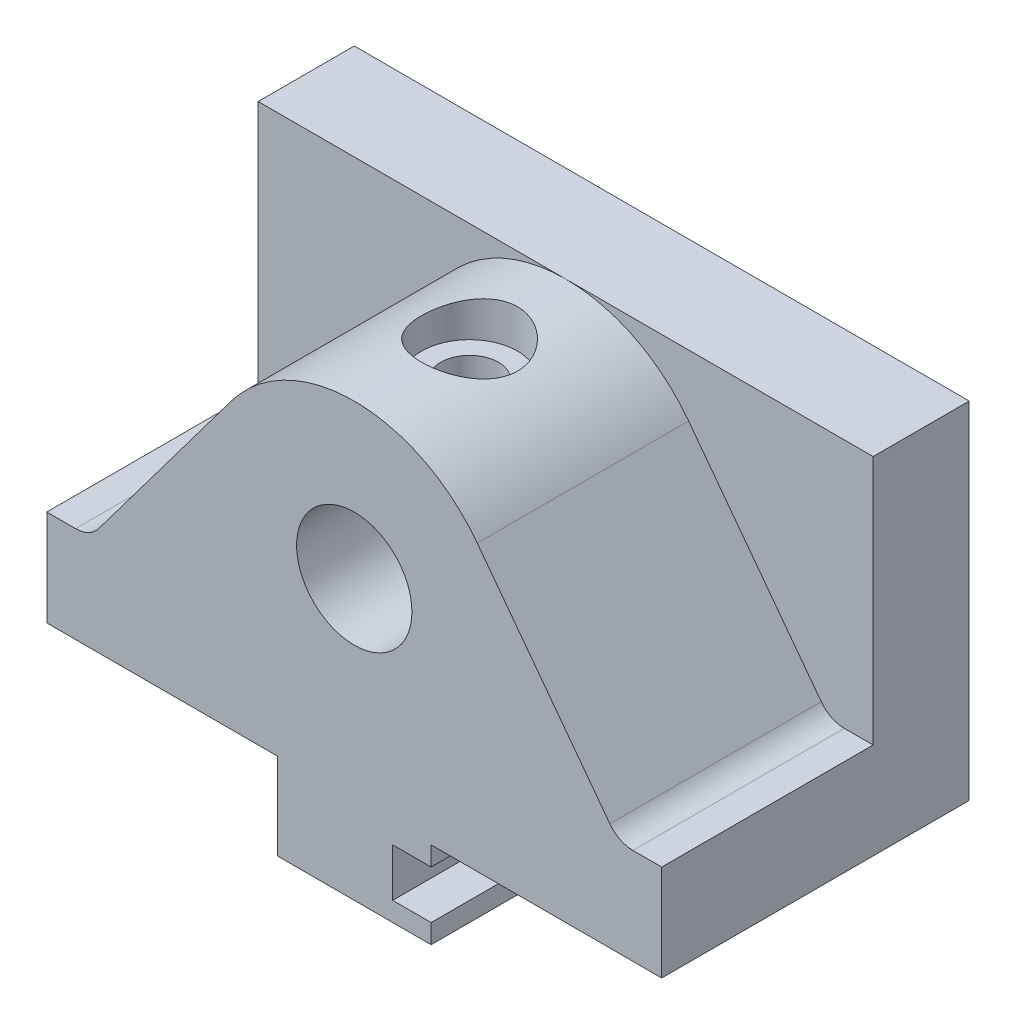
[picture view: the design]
ISO-10303-21;
HEADER;
FILE_DESCRIPTION(('STEP AP214'),'2;1');
FILE_NAME('part.step','',(''),(''),'','','');
FILE_SCHEMA(('AUTOMOTIVE_DESIGN { 1 0 10303 214 1 1 1 1 }'));
ENDSEC;
DATA;
#1=APPLICATION_CONTEXT('core data for automotive mechanical design processes');
#2=APPLICATION_PROTOCOL_DEFINITION('international standard','automotive_design',2000,#1);
#3=PRODUCT_CONTEXT('',#1,'mechanical');
#4=PRODUCT('Part','Part','',(#3));
#5=PRODUCT_RELATED_PRODUCT_CATEGORY('part','',(#4));
#6=PRODUCT_DEFINITION_FORMATION('','',#4);
#7=PRODUCT_DEFINITION_CONTEXT('part definition',#1,'design');
#8=PRODUCT_DEFINITION('design','',#6,#7);
#9=PRODUCT_DEFINITION_SHAPE('','',#8);
#10=(LENGTH_UNIT() NAMED_UNIT(*) SI_UNIT(.MILLI.,.METRE.));
#11=(NAMED_UNIT(*) PLANE_ANGLE_UNIT() SI_UNIT($,.RADIAN.));
#12=(NAMED_UNIT(*) SI_UNIT($,.STERADIAN.) SOLID_ANGLE_UNIT());
#13=UNCERTAINTY_MEASURE_WITH_UNIT(LENGTH_MEASURE(1.E-05),#10,'distance_accuracy_value','');
#14=(GEOMETRIC_REPRESENTATION_CONTEXT(3) GLOBAL_UNCERTAINTY_ASSIGNED_CONTEXT((#13)) GLOBAL_UNIT_ASSIGNED_CONTEXT((#10,
#11,#12)) REPRESENTATION_CONTEXT('',''));
#15=CARTESIAN_POINT('',(0.,0.,0.));
#16=DIRECTION('',(0.,0.,1.));
#17=DIRECTION('',(1.,0.,0.));
#18=AXIS2_PLACEMENT_3D('',#15,#16,#17);
#19=CARTESIAN_POINT('',(8.00000000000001,-14.,32.));
#20=DIRECTION('',(-1.,0.,0.));
#21=DIRECTION('',(0.,-1.,0.));
#22=AXIS2_PLACEMENT_3D('',#19,#20,#21);
#23=PLANE('',#22);
#24=DIRECTION('',(0.,1.,0.));
#25=VECTOR('',#24,1.);
#26=CARTESIAN_POINT('',(8.00000000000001,-14.,0.));
#27=LINE('',#26,#25);
#28=CARTESIAN_POINT('',(8.00000000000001,-23.,0.));
#29=VERTEX_POINT('',#28);
#30=CARTESIAN_POINT('',(8.00000000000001,-21.,0.));
#31=VERTEX_POINT('',#30);
#32=EDGE_CURVE('E383',#29,#31,#27,.T.);
#33=ORIENTED_EDGE('',*,*,#32,.T.);
#34=DIRECTION('',(0.,0.,1.));
#35=VECTOR('',#34,1.);
#36=CARTESIAN_POINT('',(8.00000000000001,-21.,0.));
#37=LINE('',#36,#35);
#38=CARTESIAN_POINT('',(8.00000000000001,-21.,32.));
#39=VERTEX_POINT('',#38);
#40=EDGE_CURVE('E406',#31,#39,#37,.T.);
#41=ORIENTED_EDGE('',*,*,#40,.T.);
#42=DIRECTION('',(0.,1.,0.));
#43=VECTOR('',#42,1.);
#44=CARTESIAN_POINT('',(8.00000000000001,-14.,32.));
#45=LINE('',#44,#43);
#46=CARTESIAN_POINT('',(8.00000000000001,-23.,32.));
#47=VERTEX_POINT('',#46);
#48=EDGE_CURVE('E209',#47,#39,#45,.T.);
#49=ORIENTED_EDGE('',*,*,#48,.F.);
#50=DIRECTION('',(0.,0.,-1.));
#51=VECTOR('',#50,1.);
#52=CARTESIAN_POINT('',(8.00000000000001,-23.,32.));
#53=LINE('',#52,#51);
#54=EDGE_CURVE('E222',#47,#29,#53,.T.);
#55=ORIENTED_EDGE('',*,*,#54,.T.);
#56=EDGE_LOOP('',(#33,#41,#49,#55));
#57=FACE_BOUND('',#56,.T.);
#58=ADVANCED_FACE('F29',(#57),#23,.F.);
#59=CARTESIAN_POINT('',(8.00000000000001,-23.,32.));
#60=DIRECTION('',(0.,1.,0.));
#61=DIRECTION('',(-1.,0.,0.));
#62=AXIS2_PLACEMENT_3D('',#59,#60,#61);
#63=PLANE('',#62);
#64=CARTESIAN_POINT('',(0.,-23.,24.));
#65=DIRECTION('',(0.,1.,0.));
#66=DIRECTION('',(-1.,0.,0.));
#67=AXIS2_PLACEMENT_3D('',#64,#65,#66);
#68=CIRCLE('',#67,3.);
#69=CARTESIAN_POINT('',(-2.99999999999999,-23.,24.));
#70=VERTEX_POINT('',#69);
#71=EDGE_CURVE('E429',#70,#70,#68,.T.);
#72=ORIENTED_EDGE('',*,*,#71,.T.);
#73=EDGE_LOOP('',(#72));
#74=FACE_BOUND('',#73,.T.);
#75=DIRECTION('',(1.,0.,0.));
#76=VECTOR('',#75,1.);
#77=CARTESIAN_POINT('',(8.00000000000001,-23.,0.));
#78=LINE('',#77,#76);
#79=CARTESIAN_POINT('',(-7.99999999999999,-23.,0.));
#80=VERTEX_POINT('',#79);
#81=EDGE_CURVE('E380',#80,#29,#78,.T.);
#82=ORIENTED_EDGE('',*,*,#81,.T.);
#83=ORIENTED_EDGE('',*,*,#54,.F.);
#84=DIRECTION('',(1.,0.,0.));
#85=VECTOR('',#84,1.);
#86=CARTESIAN_POINT('',(8.00000000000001,-23.,32.));
#87=LINE('',#86,#85);
#88=CARTESIAN_POINT('',(-7.99999999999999,-23.,32.));
#89=VERTEX_POINT('',#88);
#90=EDGE_CURVE('E210',#89,#47,#87,.T.);
#91=ORIENTED_EDGE('',*,*,#90,.F.);
#92=DIRECTION('',(0.,0.,-1.));
#93=VECTOR('',#92,1.);
#94=CARTESIAN_POINT('',(-7.99999999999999,-23.,32.));
#95=LINE('',#94,#93);
#96=EDGE_CURVE('E225',#89,#80,#95,.T.);
#97=ORIENTED_EDGE('',*,*,#96,.T.);
#98=EDGE_LOOP('',(#82,#83,#91,#97));
#99=FACE_BOUND('',#98,.T.);
#100=CARTESIAN_POINT('',(0.,-23.,8.));
#101=DIRECTION('',(0.,1.,0.));
#102=DIRECTION('',(-1.,0.,0.));
#103=AXIS2_PLACEMENT_3D('',#100,#101,#102);
#104=CIRCLE('',#103,3.);
#105=CARTESIAN_POINT('',(-2.99999999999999,-23.,8.));
#106=VERTEX_POINT('',#105);
#107=EDGE_CURVE('E423',#106,#106,#104,.T.);
#108=ORIENTED_EDGE('',*,*,#107,.T.);
#109=EDGE_LOOP('',(#108));
#110=FACE_BOUND('',#109,.T.);
#111=ADVANCED_FACE('F287',(#74,#99,#110),#63,.F.);
#112=CARTESIAN_POINT('',(32.,22.,32.));
#113=DIRECTION('',(-1.,0.,0.));
#114=DIRECTION('',(0.,-1.,0.));
#115=AXIS2_PLACEMENT_3D('',#112,#113,#114);
#116=PLANE('',#115);
#117=DIRECTION('',(0.,-1.,0.));
#118=VECTOR('',#117,1.);
#119=CARTESIAN_POINT('',(32.,22.,10.));
#120=LINE('',#119,#118);
#121=CARTESIAN_POINT('',(32.,22.,10.));
#122=VERTEX_POINT('',#121);
#123=CARTESIAN_POINT('',(32.,-4.,10.));
#124=VERTEX_POINT('',#123);
#125=EDGE_CURVE('E368',#122,#124,#120,.T.);
#126=ORIENTED_EDGE('',*,*,#125,.T.);
#127=DIRECTION('',(0.,0.,1.));
#128=VECTOR('',#127,1.);
#129=CARTESIAN_POINT('',(32.,-4.,32.));
#130=LINE('',#129,#128);
#131=CARTESIAN_POINT('',(32.,-4.,32.));
#132=VERTEX_POINT('',#131);
#133=EDGE_CURVE('E361',#124,#132,#130,.T.);
#134=ORIENTED_EDGE('',*,*,#133,.T.);
#135=DIRECTION('',(0.,1.,0.));
#136=VECTOR('',#135,1.);
#137=CARTESIAN_POINT('',(32.,22.,32.));
#138=LINE('',#137,#136);
#139=CARTESIAN_POINT('',(32.,-14.,32.));
#140=VERTEX_POINT('',#139);
#141=EDGE_CURVE('E387',#140,#132,#138,.T.);
#142=ORIENTED_EDGE('',*,*,#141,.F.);
#143=DIRECTION('',(0.,0.,-1.));
#144=VECTOR('',#143,1.);
#145=CARTESIAN_POINT('',(32.,-14.,32.));
#146=LINE('',#145,#144);
#147=CARTESIAN_POINT('',(32.,-14.,0.));
#148=VERTEX_POINT('',#147);
#149=EDGE_CURVE('E218',#140,#148,#146,.T.);
#150=ORIENTED_EDGE('',*,*,#149,.T.);
#151=DIRECTION('',(0.,1.,0.));
#152=VECTOR('',#151,1.);
#153=CARTESIAN_POINT('',(32.,22.,0.));
#154=LINE('',#153,#152);
#155=CARTESIAN_POINT('',(32.,22.,0.));
#156=VERTEX_POINT('',#155);
#157=EDGE_CURVE('E371',#148,#156,#154,.T.);
#158=ORIENTED_EDGE('',*,*,#157,.T.);
#159=DIRECTION('',(0.,0.,-1.));
#160=VECTOR('',#159,1.);
#161=CARTESIAN_POINT('',(32.,22.,32.));
#162=LINE('',#161,#160);
#163=EDGE_CURVE('E236',#122,#156,#162,.T.);
#164=ORIENTED_EDGE('',*,*,#163,.F.);
#165=EDGE_LOOP('',(#126,#134,#142,#150,#158,#164));
#166=FACE_BOUND('',#165,.T.);
#167=ADVANCED_FACE('F31',(#166),#116,.F.);
#168=CARTESIAN_POINT('',(-32.,22.,32.));
#169=DIRECTION('',(0.,-1.,0.));
#170=DIRECTION('',(1.,0.,0.));
#171=AXIS2_PLACEMENT_3D('',#168,#169,#170);
#172=PLANE('',#171);
#173=DIRECTION('',(0.,0.,-1.));
#174=VECTOR('',#173,1.);
#175=CARTESIAN_POINT('',(-32.,22.,32.));
#176=LINE('',#175,#174);
#177=CARTESIAN_POINT('',(-32.,22.,10.));
#178=VERTEX_POINT('',#177);
#179=CARTESIAN_POINT('',(-32.,22.,0.));
#180=VERTEX_POINT('',#179);
#181=EDGE_CURVE('E234',#178,#180,#176,.T.);
#182=ORIENTED_EDGE('',*,*,#181,.F.);
#183=DIRECTION('',(1.,0.,0.));
#184=VECTOR('',#183,1.);
#185=CARTESIAN_POINT('',(-32.,22.,10.));
#186=LINE('',#185,#184);
#187=CARTESIAN_POINT('',(0.,22.,10.));
#188=VERTEX_POINT('',#187);
#189=EDGE_CURVE('E328',#178,#188,#186,.T.);
#190=ORIENTED_EDGE('',*,*,#189,.T.);
#191=EDGE_CURVE('E367',#188,#122,#186,.T.);
#192=ORIENTED_EDGE('',*,*,#191,.T.);
#193=ORIENTED_EDGE('',*,*,#163,.T.);
#194=DIRECTION('',(-1.,0.,0.));
#195=VECTOR('',#194,1.);
#196=CARTESIAN_POINT('',(-32.,22.,0.));
#197=LINE('',#196,#195);
#198=EDGE_CURVE('E330',#156,#180,#197,.T.);
#199=ORIENTED_EDGE('',*,*,#198,.T.);
#200=EDGE_LOOP('',(#182,#190,#192,#193,#199));
#201=FACE_BOUND('',#200,.T.);
#202=ADVANCED_FACE('F316',(#201),#172,.F.);
#203=CARTESIAN_POINT('',(-32.,22.,32.));
#204=DIRECTION('',(1.,0.,0.));
#205=DIRECTION('',(0.,1.,0.));
#206=AXIS2_PLACEMENT_3D('',#203,#204,#205);
#207=PLANE('',#206);
#208=DIRECTION('',(0.,-1.,0.));
#209=VECTOR('',#208,1.);
#210=CARTESIAN_POINT('',(-32.,22.,32.));
#211=LINE('',#210,#209);
#212=CARTESIAN_POINT('',(-32.,-4.,32.));
#213=VERTEX_POINT('',#212);
#214=CARTESIAN_POINT('',(-32.,-14.,32.));
#215=VERTEX_POINT('',#214);
#216=EDGE_CURVE('E390',#213,#215,#211,.T.);
#217=ORIENTED_EDGE('',*,*,#216,.F.);
#218=DIRECTION('',(0.,0.,-1.));
#219=VECTOR('',#218,1.);
#220=CARTESIAN_POINT('',(-32.,-4.,32.));
#221=LINE('',#220,#219);
#222=CARTESIAN_POINT('',(-32.,-4.,10.));
#223=VERTEX_POINT('',#222);
#224=EDGE_CURVE('E337',#213,#223,#221,.T.);
#225=ORIENTED_EDGE('',*,*,#224,.T.);
#226=DIRECTION('',(0.,1.,0.));
#227=VECTOR('',#226,1.);
#228=CARTESIAN_POINT('',(-32.,22.,10.));
#229=LINE('',#228,#227);
#230=EDGE_CURVE('E243',#223,#178,#229,.T.);
#231=ORIENTED_EDGE('',*,*,#230,.T.);
#232=ORIENTED_EDGE('',*,*,#181,.T.);
#233=DIRECTION('',(0.,-1.,0.));
#234=VECTOR('',#233,1.);
#235=CARTESIAN_POINT('',(-32.,22.,0.));
#236=LINE('',#235,#234);
#237=CARTESIAN_POINT('',(-32.,-14.,0.));
#238=VERTEX_POINT('',#237);
#239=EDGE_CURVE('E334',#180,#238,#236,.T.);
#240=ORIENTED_EDGE('',*,*,#239,.T.);
#241=DIRECTION('',(0.,0.,-1.));
#242=VECTOR('',#241,1.);
#243=CARTESIAN_POINT('',(-32.,-14.,32.));
#244=LINE('',#243,#242);
#245=EDGE_CURVE('E231',#215,#238,#244,.T.);
#246=ORIENTED_EDGE('',*,*,#245,.F.);
#247=EDGE_LOOP('',(#217,#225,#231,#232,#240,#246));
#248=FACE_BOUND('',#247,.T.);
#249=ADVANCED_FACE('F311',(#248),#207,.F.);
#250=CARTESIAN_POINT('',(-32.,-14.,32.));
#251=DIRECTION('',(0.,1.,0.));
#252=DIRECTION('',(-1.,0.,0.));
#253=AXIS2_PLACEMENT_3D('',#250,#251,#252);
#254=PLANE('',#253);
#255=DIRECTION('',(1.,0.,0.));
#256=VECTOR('',#255,1.);
#257=CARTESIAN_POINT('',(-32.,-14.,0.));
#258=LINE('',#257,#256);
#259=CARTESIAN_POINT('',(-7.99999999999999,-14.,0.));
#260=VERTEX_POINT('',#259);
#261=EDGE_CURVE('E376',#238,#260,#258,.T.);
#262=ORIENTED_EDGE('',*,*,#261,.T.);
#263=DIRECTION('',(0.,0.,-1.));
#264=VECTOR('',#263,1.);
#265=CARTESIAN_POINT('',(-7.99999999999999,-14.,32.));
#266=LINE('',#265,#264);
#267=CARTESIAN_POINT('',(-7.99999999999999,-14.,32.));
#268=VERTEX_POINT('',#267);
#269=EDGE_CURVE('E228',#268,#260,#266,.T.);
#270=ORIENTED_EDGE('',*,*,#269,.F.);
#271=DIRECTION('',(1.,0.,0.));
#272=VECTOR('',#271,1.);
#273=CARTESIAN_POINT('',(-32.,-14.,32.));
#274=LINE('',#273,#272);
#275=EDGE_CURVE('E392',#215,#268,#274,.T.);
#276=ORIENTED_EDGE('',*,*,#275,.F.);
#277=ORIENTED_EDGE('',*,*,#245,.T.);
#278=EDGE_LOOP('',(#262,#270,#276,#277));
#279=FACE_BOUND('',#278,.T.);
#280=ADVANCED_FACE('F305',(#279),#254,.F.);
#281=CARTESIAN_POINT('',(-7.99999999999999,-14.,32.));
#282=DIRECTION('',(1.,0.,0.));
#283=DIRECTION('',(0.,1.,0.));
#284=AXIS2_PLACEMENT_3D('',#281,#282,#283);
#285=PLANE('',#284);
#286=DIRECTION('',(0.,-1.,0.));
#287=VECTOR('',#286,1.);
#288=CARTESIAN_POINT('',(-7.99999999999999,-14.,0.));
#289=LINE('',#288,#287);
#290=EDGE_CURVE('E378',#260,#80,#289,.T.);
#291=ORIENTED_EDGE('',*,*,#290,.T.);
#292=ORIENTED_EDGE('',*,*,#96,.F.);
#293=DIRECTION('',(0.,-1.,0.));
#294=VECTOR('',#293,1.);
#295=CARTESIAN_POINT('',(-7.99999999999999,-14.,32.));
#296=LINE('',#295,#294);
#297=EDGE_CURVE('E213',#268,#89,#296,.T.);
#298=ORIENTED_EDGE('',*,*,#297,.F.);
#299=ORIENTED_EDGE('',*,*,#269,.T.);
#300=EDGE_LOOP('',(#291,#292,#298,#299));
#301=FACE_BOUND('',#300,.T.);
#302=ADVANCED_FACE('F299',(#301),#285,.F.);
#303=CARTESIAN_POINT('',(8.00000000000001,-16.,32.));
#304=VERTEX_POINT('',#303);
#305=CARTESIAN_POINT('',(8.00000000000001,-14.,32.));
#306=VERTEX_POINT('',#305);
#307=EDGE_CURVE('E199',#304,#306,#45,.T.);
#308=ORIENTED_EDGE('',*,*,#307,.F.);
#309=DIRECTION('',(0.,0.,1.));
#310=VECTOR('',#309,1.);
#311=CARTESIAN_POINT('',(8.00000000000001,-16.,0.));
#312=LINE('',#311,#310);
#313=CARTESIAN_POINT('',(8.00000000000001,-16.,0.));
#314=VERTEX_POINT('',#313);
#315=EDGE_CURVE('E183',#314,#304,#312,.T.);
#316=ORIENTED_EDGE('',*,*,#315,.F.);
#317=CARTESIAN_POINT('',(8.00000000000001,-14.,0.));
#318=VERTEX_POINT('',#317);
#319=EDGE_CURVE('E382',#314,#318,#27,.T.);
#320=ORIENTED_EDGE('',*,*,#319,.T.);
#321=DIRECTION('',(0.,0.,-1.));
#322=VECTOR('',#321,1.);
#323=CARTESIAN_POINT('',(8.00000000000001,-14.,32.));
#324=LINE('',#323,#322);
#325=EDGE_CURVE('E207',#306,#318,#324,.T.);
#326=ORIENTED_EDGE('',*,*,#325,.F.);
#327=EDGE_LOOP('',(#308,#316,#320,#326));
#328=FACE_BOUND('',#327,.T.);
#329=ADVANCED_FACE('F205',(#328),#23,.F.);
#330=CARTESIAN_POINT('',(32.,-14.,32.));
#331=DIRECTION('',(0.,1.,0.));
#332=DIRECTION('',(-1.,0.,0.));
#333=AXIS2_PLACEMENT_3D('',#330,#331,#332);
#334=PLANE('',#333);
#335=DIRECTION('',(1.,0.,0.));
#336=VECTOR('',#335,1.);
#337=CARTESIAN_POINT('',(32.,-14.,0.));
#338=LINE('',#337,#336);
#339=EDGE_CURVE('E385',#318,#148,#338,.T.);
#340=ORIENTED_EDGE('',*,*,#339,.T.);
#341=ORIENTED_EDGE('',*,*,#149,.F.);
#342=DIRECTION('',(1.,0.,0.));
#343=VECTOR('',#342,1.);
#344=CARTESIAN_POINT('',(32.,-14.,32.));
#345=LINE('',#344,#343);
#346=EDGE_CURVE('E212',#306,#140,#345,.T.);
#347=ORIENTED_EDGE('',*,*,#346,.F.);
#348=ORIENTED_EDGE('',*,*,#325,.T.);
#349=EDGE_LOOP('',(#340,#341,#347,#348));
#350=FACE_BOUND('',#349,.T.);
#351=ADVANCED_FACE('F298',(#350),#334,.F.);
#352=CARTESIAN_POINT('',(32.,-23.,32.));
#353=DIRECTION('',(0.,0.,-1.));
#354=DIRECTION('',(-1.,0.,0.));
#355=AXIS2_PLACEMENT_3D('',#352,#353,#354);
#356=PLANE('',#355);
#357=CARTESIAN_POINT('',(0.,6.,32.));
#358=DIRECTION('',(0.,0.,1.));
#359=DIRECTION('',(1.,0.,0.));
#360=AXIS2_PLACEMENT_3D('',#357,#358,#359);
#361=CIRCLE('',#360,6.);
#362=CARTESIAN_POINT('',(6.,6.,32.));
#363=VERTEX_POINT('',#362);
#364=EDGE_CURVE('E444',#363,#363,#361,.T.);
#365=ORIENTED_EDGE('',*,*,#364,.F.);
#366=EDGE_LOOP('',(#365));
#367=FACE_BOUND('',#366,.T.);
#368=ORIENTED_EDGE('',*,*,#48,.T.);
#369=DIRECTION('',(1.,0.,0.));
#370=VECTOR('',#369,1.);
#371=CARTESIAN_POINT('',(8.00000000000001,-21.,32.));
#372=LINE('',#371,#370);
#373=CARTESIAN_POINT('',(4.00000000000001,-21.,32.));
#374=VERTEX_POINT('',#373);
#375=EDGE_CURVE('E407',#374,#39,#372,.T.);
#376=ORIENTED_EDGE('',*,*,#375,.F.);
#377=DIRECTION('',(0.,-1.,0.));
#378=VECTOR('',#377,1.);
#379=CARTESIAN_POINT('',(4.00000000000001,-16.,32.));
#380=LINE('',#379,#378);
#381=CARTESIAN_POINT('',(4.00000000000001,-16.,32.));
#382=VERTEX_POINT('',#381);
#383=EDGE_CURVE('E203',#382,#374,#380,.T.);
#384=ORIENTED_EDGE('',*,*,#383,.F.);
#385=DIRECTION('',(-1.,0.,0.));
#386=VECTOR('',#385,1.);
#387=CARTESIAN_POINT('',(8.00000000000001,-16.,32.));
#388=LINE('',#387,#386);
#389=EDGE_CURVE('E186',#304,#382,#388,.T.);
#390=ORIENTED_EDGE('',*,*,#389,.F.);
#391=ORIENTED_EDGE('',*,*,#307,.T.);
#392=ORIENTED_EDGE('',*,*,#346,.T.);
#393=ORIENTED_EDGE('',*,*,#141,.T.);
#394=DIRECTION('',(1.,0.,0.));
#395=VECTOR('',#394,1.);
#396=CARTESIAN_POINT('',(38.9732794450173,-4.,32.));
#397=LINE('',#396,#395);
#398=CARTESIAN_POINT('',(29.,-4.,32.));
#399=VERTEX_POINT('',#398);
#400=EDGE_CURVE('E474',#399,#132,#397,.T.);
#401=ORIENTED_EDGE('',*,*,#400,.F.);
#402=CARTESIAN_POINT('',(29.,-0.999999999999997,32.));
#403=DIRECTION('',(0.,0.,-1.));
#404=DIRECTION('',(-1.,0.,0.));
#405=AXIS2_PLACEMENT_3D('',#402,#403,#404);
#406=CIRCLE('',#405,3.);
#407=CARTESIAN_POINT('',(26.6,-2.8,32.));
#408=VERTEX_POINT('',#407);
#409=EDGE_CURVE('E261',#399,#408,#406,.T.);
#410=ORIENTED_EDGE('',*,*,#409,.T.);
#411=DIRECTION('',(0.6,-0.8,0.));
#412=VECTOR('',#411,1.);
#413=CARTESIAN_POINT('',(12.8,15.6,32.));
#414=LINE('',#413,#412);
#415=CARTESIAN_POINT('',(12.8,15.6,32.));
#416=VERTEX_POINT('',#415);
#417=EDGE_CURVE('E473',#416,#408,#414,.T.);
#418=ORIENTED_EDGE('',*,*,#417,.F.);
#419=CARTESIAN_POINT('',(0.,6.,32.));
#420=DIRECTION('',(0.,0.,-1.));
#421=DIRECTION('',(-1.,0.,0.));
#422=AXIS2_PLACEMENT_3D('',#419,#420,#421);
#423=CIRCLE('',#422,16.);
#424=CARTESIAN_POINT('',(-12.8,15.6,32.));
#425=VERTEX_POINT('',#424);
#426=EDGE_CURVE('E238',#416,#425,#423,.F.);
#427=ORIENTED_EDGE('',*,*,#426,.T.);
#428=DIRECTION('',(0.6,0.8,0.));
#429=VECTOR('',#428,1.);
#430=CARTESIAN_POINT('',(-12.8,15.6,32.));
#431=LINE('',#430,#429);
#432=CARTESIAN_POINT('',(-26.6,-2.80000000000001,32.));
#433=VERTEX_POINT('',#432);
#434=EDGE_CURVE('E478',#433,#425,#431,.T.);
#435=ORIENTED_EDGE('',*,*,#434,.F.);
#436=CARTESIAN_POINT('',(-29.,-1.00000000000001,32.));
#437=DIRECTION('',(0.,0.,-1.));
#438=DIRECTION('',(-1.,0.,0.));
#439=AXIS2_PLACEMENT_3D('',#436,#437,#438);
#440=CIRCLE('',#439,3.);
#441=CARTESIAN_POINT('',(-29.,-4.00000000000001,32.));
#442=VERTEX_POINT('',#441);
#443=EDGE_CURVE('E260',#433,#442,#440,.T.);
#444=ORIENTED_EDGE('',*,*,#443,.T.);
#445=DIRECTION('',(-1.,0.,0.));
#446=VECTOR('',#445,1.);
#447=CARTESIAN_POINT('',(32.,-4.00000000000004,32.));
#448=LINE('',#447,#446);
#449=EDGE_CURVE('E241',#442,#213,#448,.T.);
#450=ORIENTED_EDGE('',*,*,#449,.T.);
#451=ORIENTED_EDGE('',*,*,#216,.T.);
#452=ORIENTED_EDGE('',*,*,#275,.T.);
#453=ORIENTED_EDGE('',*,*,#297,.T.);
#454=ORIENTED_EDGE('',*,*,#90,.T.);
#455=EDGE_LOOP('',(#368,#376,#384,#390,#391,#392,#393,#401,#410,#418,#427,#435,#444,#450,#451,
#452,#453,#454));
#456=FACE_BOUND('',#455,.T.);
#457=ADVANCED_FACE('F198',(#367,#456),#356,.F.);
#458=CARTESIAN_POINT('',(32.,-23.,0.));
#459=DIRECTION('',(0.,0.,-1.));
#460=DIRECTION('',(-1.,0.,0.));
#461=AXIS2_PLACEMENT_3D('',#458,#459,#460);
#462=PLANE('',#461);
#463=DIRECTION('',(1.,0.,0.));
#464=VECTOR('',#463,1.);
#465=CARTESIAN_POINT('',(8.00000000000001,-21.,0.));
#466=LINE('',#465,#464);
#467=CARTESIAN_POINT('',(4.00000000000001,-21.,0.));
#468=VERTEX_POINT('',#467);
#469=EDGE_CURVE('E194',#468,#31,#466,.T.);
#470=ORIENTED_EDGE('',*,*,#469,.T.);
#471=ORIENTED_EDGE('',*,*,#32,.F.);
#472=ORIENTED_EDGE('',*,*,#81,.F.);
#473=ORIENTED_EDGE('',*,*,#290,.F.);
#474=ORIENTED_EDGE('',*,*,#261,.F.);
#475=ORIENTED_EDGE('',*,*,#239,.F.);
#476=ORIENTED_EDGE('',*,*,#198,.F.);
#477=ORIENTED_EDGE('',*,*,#157,.F.);
#478=ORIENTED_EDGE('',*,*,#339,.F.);
#479=ORIENTED_EDGE('',*,*,#319,.F.);
#480=DIRECTION('',(-1.,0.,0.));
#481=VECTOR('',#480,1.);
#482=CARTESIAN_POINT('',(8.00000000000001,-16.,0.));
#483=LINE('',#482,#481);
#484=CARTESIAN_POINT('',(4.00000000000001,-16.,0.));
#485=VERTEX_POINT('',#484);
#486=EDGE_CURVE('E189',#314,#485,#483,.T.);
#487=ORIENTED_EDGE('',*,*,#486,.T.);
#488=DIRECTION('',(0.,-1.,0.));
#489=VECTOR('',#488,1.);
#490=CARTESIAN_POINT('',(4.00000000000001,-16.,0.));
#491=LINE('',#490,#489);
#492=EDGE_CURVE('E48',#485,#468,#491,.T.);
#493=ORIENTED_EDGE('',*,*,#492,.T.);
#494=EDGE_LOOP('',(#470,#471,#472,#473,#474,#475,#476,#477,#478,#479,#487,#493));
#495=FACE_BOUND('',#494,.T.);
#496=ADVANCED_FACE('F502',(#495),#462,.T.);
#497=CARTESIAN_POINT('',(0.,6.,10.));
#498=DIRECTION('',(0.,0.,-1.));
#499=DIRECTION('',(-1.,0.,0.));
#500=AXIS2_PLACEMENT_3D('',#497,#498,#499);
#501=PLANE('',#500);
#502=DIRECTION('',(0.6,-0.8,0.));
#503=VECTOR('',#502,1.);
#504=CARTESIAN_POINT('',(12.8,15.6,10.));
#505=LINE('',#504,#503);
#506=CARTESIAN_POINT('',(12.8,15.6,10.));
#507=VERTEX_POINT('',#506);
#508=CARTESIAN_POINT('',(26.6,-2.8,10.));
#509=VERTEX_POINT('',#508);
#510=EDGE_CURVE('E354',#507,#509,#505,.T.);
#511=ORIENTED_EDGE('',*,*,#510,.T.);
#512=CARTESIAN_POINT('',(29.,-0.999999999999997,10.));
#513=DIRECTION('',(0.,0.,-1.));
#514=DIRECTION('',(-1.,0.,0.));
#515=AXIS2_PLACEMENT_3D('',#512,#513,#514);
#516=CIRCLE('',#515,3.);
#517=CARTESIAN_POINT('',(29.,-4.,10.));
#518=VERTEX_POINT('',#517);
#519=EDGE_CURVE('E258',#509,#518,#516,.F.);
#520=ORIENTED_EDGE('',*,*,#519,.T.);
#521=DIRECTION('',(1.,0.,0.));
#522=VECTOR('',#521,1.);
#523=CARTESIAN_POINT('',(27.5,-4.,10.));
#524=LINE('',#523,#522);
#525=EDGE_CURVE('E350',#518,#124,#524,.T.);
#526=ORIENTED_EDGE('',*,*,#525,.T.);
#527=ORIENTED_EDGE('',*,*,#125,.F.);
#528=ORIENTED_EDGE('',*,*,#191,.F.);
#529=CARTESIAN_POINT('',(0.,6.,10.));
#530=DIRECTION('',(0.,0.,-1.));
#531=DIRECTION('',(-1.,0.,0.));
#532=AXIS2_PLACEMENT_3D('',#529,#530,#531);
#533=CIRCLE('',#532,16.);
#534=EDGE_CURVE('E480',#188,#507,#533,.T.);
#535=ORIENTED_EDGE('',*,*,#534,.T.);
#536=EDGE_LOOP('',(#511,#520,#526,#527,#528,#535));
#537=FACE_BOUND('',#536,.T.);
#538=ADVANCED_FACE('F486',(#537),#501,.F.);
#539=DIRECTION('',(1.,0.,0.));
#540=VECTOR('',#539,1.);
#541=CARTESIAN_POINT('',(-32.,-4.,10.));
#542=LINE('',#541,#540);
#543=CARTESIAN_POINT('',(-29.,-4.,10.));
#544=VERTEX_POINT('',#543);
#545=EDGE_CURVE('E342',#223,#544,#542,.T.);
#546=ORIENTED_EDGE('',*,*,#545,.T.);
#547=CARTESIAN_POINT('',(-29.,-1.00000000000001,10.));
#548=DIRECTION('',(0.,0.,-1.));
#549=DIRECTION('',(-1.,0.,0.));
#550=AXIS2_PLACEMENT_3D('',#547,#548,#549);
#551=CIRCLE('',#550,3.);
#552=CARTESIAN_POINT('',(-26.6,-2.80000000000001,10.));
#553=VERTEX_POINT('',#552);
#554=EDGE_CURVE('E251',#544,#553,#551,.F.);
#555=ORIENTED_EDGE('',*,*,#554,.T.);
#556=DIRECTION('',(0.6,0.8,0.));
#557=VECTOR('',#556,1.);
#558=CARTESIAN_POINT('',(-12.8,15.6,10.));
#559=LINE('',#558,#557);
#560=CARTESIAN_POINT('',(-12.8,15.6,10.));
#561=VERTEX_POINT('',#560);
#562=EDGE_CURVE('E349',#553,#561,#559,.T.);
#563=ORIENTED_EDGE('',*,*,#562,.T.);
#564=EDGE_CURVE('E481',#561,#188,#533,.T.);
#565=ORIENTED_EDGE('',*,*,#564,.T.);
#566=ORIENTED_EDGE('',*,*,#189,.F.);
#567=ORIENTED_EDGE('',*,*,#230,.F.);
#568=EDGE_LOOP('',(#546,#555,#563,#565,#566,#567));
#569=FACE_BOUND('',#568,.T.);
#570=ADVANCED_FACE('F341',(#569),#501,.F.);
#571=CARTESIAN_POINT('',(0.,6.,10.));
#572=DIRECTION('',(0.,0.,1.));
#573=DIRECTION('',(1.,0.,0.));
#574=AXIS2_PLACEMENT_3D('',#571,#572,#573);
#575=CYLINDRICAL_SURFACE('',#574,16.);
#576=CARTESIAN_POINT('',(0.,22.,25.));
#577=CARTESIAN_POINT('',(-0.273756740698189,21.9999986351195,24.9999982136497));
#578=CARTESIAN_POINT('',(-0.54753221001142,21.9929077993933,24.9774430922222));
#579=CARTESIAN_POINT('',(-1.08707683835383,21.9653157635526,24.888055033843));
#580=CARTESIAN_POINT('',(-1.35284417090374,21.9448115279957,24.8212120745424));
#581=CARTESIAN_POINT('',(-1.86851417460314,21.892632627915,24.6457225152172));
#582=CARTESIAN_POINT('',(-2.11844070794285,21.860975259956,24.5371406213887));
#583=CARTESIAN_POINT('',(-2.59653920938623,21.7897587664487,24.2815307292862));
#584=CARTESIAN_POINT('',(-2.82470774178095,21.7501983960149,24.1344966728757));
#585=CARTESIAN_POINT('',(-3.25986133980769,21.6660085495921,23.8013760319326));
#586=CARTESIAN_POINT('',(-3.4660801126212,21.621268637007,23.6143164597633));
#587=CARTESIAN_POINT('',(-3.84478952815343,21.5324018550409,23.2085264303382));
#588=CARTESIAN_POINT('',(-4.01727389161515,21.4882751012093,22.9897900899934));
#589=CARTESIAN_POINT('',(-4.32777345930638,21.4044457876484,22.5202217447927));
#590=CARTESIAN_POINT('',(-4.46483136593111,21.3648795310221,22.2687300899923));
#591=CARTESIAN_POINT('',(-4.69438964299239,21.2963120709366,21.7448307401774));
#592=CARTESIAN_POINT('',(-4.78690175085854,21.2673080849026,21.4724285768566));
#593=CARTESIAN_POINT('',(-4.92193839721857,21.224304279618,20.9230876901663));
#594=CARTESIAN_POINT('',(-4.96588440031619,21.2098789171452,20.6465326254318));
#595=CARTESIAN_POINT('',(-5.00698220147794,21.1964022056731,20.0896275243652));
#596=CARTESIAN_POINT('',(-5.00414643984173,21.1973467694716,19.809278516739));
#597=CARTESIAN_POINT('',(-4.95287298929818,21.2141275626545,19.2645021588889));
#598=CARTESIAN_POINT('',(-4.90624231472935,21.2293736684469,18.9998834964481));
#599=CARTESIAN_POINT('',(-4.77163253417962,21.272081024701,18.482431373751));
#600=CARTESIAN_POINT('',(-4.68364903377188,21.2995435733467,18.2295991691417));
#601=CARTESIAN_POINT('',(-4.46755498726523,21.3640417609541,17.7385922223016));
#602=CARTESIAN_POINT('',(-4.33887702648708,21.4012113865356,17.5006855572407));
#603=CARTESIAN_POINT('',(-4.04544082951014,21.4808742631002,17.0492489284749));
#604=CARTESIAN_POINT('',(-3.88067322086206,21.523368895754,16.8357253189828));
#605=CARTESIAN_POINT('',(-3.51086781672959,21.6112611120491,16.4289002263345));
#606=CARTESIAN_POINT('',(-3.30433828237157,21.6567027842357,16.2369617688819));
#607=CARTESIAN_POINT('',(-2.86145763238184,21.7436628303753,15.8901124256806));
#608=CARTESIAN_POINT('',(-2.62510430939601,21.7851809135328,15.735204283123));
#609=CARTESIAN_POINT('',(-2.12665844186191,21.8600517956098,15.4658892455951));
#610=CARTESIAN_POINT('',(-1.86437962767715,21.8933384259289,15.3518074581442));
#611=CARTESIAN_POINT('',(-1.32307191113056,21.9475182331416,15.1697879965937));
#612=CARTESIAN_POINT('',(-1.04404812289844,21.9684151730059,15.1018363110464));
#613=CARTESIAN_POINT('',(-0.488740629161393,21.9948555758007,15.0163278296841));
#614=CARTESIAN_POINT('',(-0.212767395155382,22.0009609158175,14.9969258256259));
#615=CARTESIAN_POINT('',(0.338521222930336,21.9987919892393,15.0038649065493));
#616=CARTESIAN_POINT('',(0.613836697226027,21.9905198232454,15.0301993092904));
#617=CARTESIAN_POINT('',(1.14887733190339,21.9608945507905,15.1263823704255));
#618=CARTESIAN_POINT('',(1.40881991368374,21.9398717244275,15.1951330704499));
#619=CARTESIAN_POINT('',(1.9134077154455,21.8872048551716,15.3728574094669));
#620=CARTESIAN_POINT('',(2.15805104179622,21.8555595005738,15.4818360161));
#621=CARTESIAN_POINT('',(2.63172962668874,21.783941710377,15.7398928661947));
#622=CARTESIAN_POINT('',(2.86023895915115,21.7437850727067,15.8898839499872));
#623=CARTESIAN_POINT('',(3.28946340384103,21.6597364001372,16.2246128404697));
#624=CARTESIAN_POINT('',(3.49017095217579,21.6158433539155,16.4093600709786));
#625=CARTESIAN_POINT('',(3.86634985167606,21.5270797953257,16.8170355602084));
#626=CARTESIAN_POINT('',(4.04050609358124,21.4822394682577,17.0411866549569));
#627=CARTESIAN_POINT('',(4.34885000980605,21.3984778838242,17.5165064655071));
#628=CARTESIAN_POINT('',(4.48303831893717,21.3595565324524,17.7676747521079));
#629=CARTESIAN_POINT('',(4.70680333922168,21.2924712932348,18.2893806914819));
#630=CARTESIAN_POINT('',(4.79655278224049,21.264265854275,18.5598385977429));
#631=CARTESIAN_POINT('',(4.9289157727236,21.2220468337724,19.1130899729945));
#632=CARTESIAN_POINT('',(4.97154725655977,21.2080278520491,19.3958787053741));
#633=CARTESIAN_POINT('',(5.00717624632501,21.1963317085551,19.9520163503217));
#634=CARTESIAN_POINT('',(5.00233118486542,21.1979441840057,20.2252138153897));
#635=CARTESIAN_POINT('',(4.94835272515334,21.2156036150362,20.7666983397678));
#636=CARTESIAN_POINT('',(4.89922139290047,21.2316498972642,21.0349856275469));
#637=CARTESIAN_POINT('',(4.75950919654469,21.2758725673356,21.5551761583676));
#638=CARTESIAN_POINT('',(4.66954569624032,21.3038679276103,21.8072617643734));
#639=CARTESIAN_POINT('',(4.45120909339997,21.3687881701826,22.292961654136));
#640=CARTESIAN_POINT('',(4.32282817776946,21.4057148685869,22.5265721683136));
#641=CARTESIAN_POINT('',(4.02542700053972,21.4861394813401,22.9785838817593));
#642=CARTESIAN_POINT('',(3.85501334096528,21.5298379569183,23.196032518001));
#643=CARTESIAN_POINT('',(3.48083598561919,21.6179599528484,23.599945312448));
#644=CARTESIAN_POINT('',(3.27706336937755,21.6623836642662,23.7864011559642));
#645=CARTESIAN_POINT('',(2.83394665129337,21.7486908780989,24.1291301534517));
#646=CARTESIAN_POINT('',(2.59365829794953,21.7904440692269,24.2842189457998));
#647=CARTESIAN_POINT('',(2.08911655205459,21.8650707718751,24.5515956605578));
#648=CARTESIAN_POINT('',(1.82487263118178,21.8979477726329,24.6639004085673));
#649=CARTESIAN_POINT('',(1.3029905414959,21.9488260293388,24.8343654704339));
#650=CARTESIAN_POINT('',(1.04668134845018,21.9678496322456,24.8962994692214));
#651=CARTESIAN_POINT('',(0.526919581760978,21.9934360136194,24.9791134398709));
#652=CARTESIAN_POINT('',(0.263468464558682,22.0000013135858,25.000001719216));
#653=CARTESIAN_POINT('',(0.,22.,25.));
#654=B_SPLINE_CURVE_WITH_KNOTS('',3,(#576,#577,#578,#579,#580,#581,#582,#583,#584,#585,#586,
#587,#588,#589,#590,#591,#592,#593,#594,#595,#596,#597,#598,#599,#600,#601,#602,#603,#604,#605,
#606,#607,#608,#609,#610,#611,#612,#613,#614,#615,#616,#617,#618,#619,#620,#621,#622,#623,#624,
#625,#626,#627,#628,#629,#630,#631,#632,#633,#634,#635,#636,#637,#638,#639,#640,#641,#642,#643,
#644,#645,#646,#647,#648,#649,#650,#651,#652,#653),.UNSPECIFIED.,.T.,.F.,(4,2,2,2,2,2,2,2,2,2,2,
2,2,2,2,2,2,2,2,2,2,2,2,2,2,2,2,2,2,2,2,2,2,2,2,2,2,2,4),(0.,0.82030179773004,1.64078929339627,
2.46000991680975,3.27935968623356,4.12151288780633,4.96382269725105,5.82695084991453,
6.68985145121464,7.52676600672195,8.36345801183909,9.16707669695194,9.97078079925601,
10.7862257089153,11.6018826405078,12.4546698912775,13.3075202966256,14.1670184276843,
15.0262553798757,15.852302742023,16.678229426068,17.4836250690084,18.2891202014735,
19.1142529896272,19.9396098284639,20.7976711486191,21.655718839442,22.5104046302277,
23.3647649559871,24.1804881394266,24.9961732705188,25.7999165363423,26.6038233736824,
27.4391805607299,28.274761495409,29.1376267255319,30.0001522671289,30.789785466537,
31.5792588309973),.UNSPECIFIED.);
#655=CARTESIAN_POINT('',(0.,22.,15.));
#656=VERTEX_POINT('',#655);
#657=CARTESIAN_POINT('',(0.,22.,25.));
#658=VERTEX_POINT('',#657);
#659=EDGE_CURVE('E33',#656,#658,#654,.T.);
#660=ORIENTED_EDGE('',*,*,#659,.T.);
#661=EDGE_CURVE('E11',#658,#656,#654,.T.);
#662=ORIENTED_EDGE('',*,*,#661,.T.);
#663=EDGE_LOOP('',(#660,#662));
#664=FACE_BOUND('',#663,.T.);
#665=ORIENTED_EDGE('',*,*,#426,.F.);
#666=DIRECTION('',(0.,0.,1.));
#667=VECTOR('',#666,1.);
#668=CARTESIAN_POINT('',(12.8,15.6,10.));
#669=LINE('',#668,#667);
#670=EDGE_CURVE('E352',#507,#416,#669,.T.);
#671=ORIENTED_EDGE('',*,*,#670,.F.);
#672=ORIENTED_EDGE('',*,*,#534,.F.);
#673=ORIENTED_EDGE('',*,*,#564,.F.);
#674=DIRECTION('',(0.,0.,1.));
#675=VECTOR('',#674,1.);
#676=CARTESIAN_POINT('',(-12.8,15.6,10.));
#677=LINE('',#676,#675);
#678=EDGE_CURVE('E358',#561,#425,#677,.T.);
#679=ORIENTED_EDGE('',*,*,#678,.T.);
#680=EDGE_LOOP('',(#665,#671,#672,#673,#679));
#681=FACE_BOUND('',#680,.T.);
#682=ADVANCED_FACE('F266',(#664,#681),#575,.T.);
#683=CARTESIAN_POINT('',(-27.5,-4.00000000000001,10.));
#684=DIRECTION('',(0.,-1.,0.));
#685=DIRECTION('',(1.,0.,0.));
#686=AXIS2_PLACEMENT_3D('',#683,#684,#685);
#687=PLANE('',#686);
#688=ORIENTED_EDGE('',*,*,#449,.F.);
#689=DIRECTION('',(0.,0.,1.));
#690=VECTOR('',#689,1.);
#691=CARTESIAN_POINT('',(-29.,-4.00000000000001,10.));
#692=LINE('',#691,#690);
#693=EDGE_CURVE('E249',#442,#544,#692,.F.);
#694=ORIENTED_EDGE('',*,*,#693,.T.);
#695=ORIENTED_EDGE('',*,*,#545,.F.);
#696=ORIENTED_EDGE('',*,*,#224,.F.);
#697=EDGE_LOOP('',(#688,#694,#695,#696));
#698=FACE_BOUND('',#697,.T.);
#699=ADVANCED_FACE('F347',(#698),#687,.F.);
#700=CARTESIAN_POINT('',(38.9732794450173,-4.,10.));
#701=DIRECTION('',(0.,-1.,0.));
#702=DIRECTION('',(0.,0.,-1.));
#703=AXIS2_PLACEMENT_3D('',#700,#701,#702);
#704=PLANE('',#703);
#705=ORIENTED_EDGE('',*,*,#525,.F.);
#706=DIRECTION('',(0.,0.,1.));
#707=VECTOR('',#706,1.);
#708=CARTESIAN_POINT('',(29.,-4.,32.));
#709=LINE('',#708,#707);
#710=EDGE_CURVE('E253',#518,#399,#709,.T.);
#711=ORIENTED_EDGE('',*,*,#710,.T.);
#712=ORIENTED_EDGE('',*,*,#400,.T.);
#713=ORIENTED_EDGE('',*,*,#133,.F.);
#714=EDGE_LOOP('',(#705,#711,#712,#713));
#715=FACE_BOUND('',#714,.T.);
#716=ADVANCED_FACE('F495',(#715),#704,.F.);
#717=CARTESIAN_POINT('',(-12.8,15.6,10.));
#718=DIRECTION('',(0.8,-0.6,0.));
#719=DIRECTION('',(0.6,0.8,0.));
#720=AXIS2_PLACEMENT_3D('',#717,#718,#719);
#721=PLANE('',#720);
#722=ORIENTED_EDGE('',*,*,#562,.F.);
#723=DIRECTION('',(0.,0.,1.));
#724=VECTOR('',#723,1.);
#725=CARTESIAN_POINT('',(-26.6,-2.80000000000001,32.));
#726=LINE('',#725,#724);
#727=EDGE_CURVE('E246',#553,#433,#726,.T.);
#728=ORIENTED_EDGE('',*,*,#727,.T.);
#729=ORIENTED_EDGE('',*,*,#434,.T.);
#730=ORIENTED_EDGE('',*,*,#678,.F.);
#731=EDGE_LOOP('',(#722,#728,#729,#730));
#732=FACE_BOUND('',#731,.T.);
#733=ADVANCED_FACE('F512',(#732),#721,.F.);
#734=CARTESIAN_POINT('',(12.8,15.6,10.));
#735=DIRECTION('',(-0.8,-0.6,0.));
#736=DIRECTION('',(0.6,-0.8,0.));
#737=AXIS2_PLACEMENT_3D('',#734,#735,#736);
#738=PLANE('',#737);
#739=ORIENTED_EDGE('',*,*,#417,.T.);
#740=DIRECTION('',(0.,0.,1.));
#741=VECTOR('',#740,1.);
#742=CARTESIAN_POINT('',(26.6,-2.8,10.));
#743=LINE('',#742,#741);
#744=EDGE_CURVE('E256',#408,#509,#743,.F.);
#745=ORIENTED_EDGE('',*,*,#744,.T.);
#746=ORIENTED_EDGE('',*,*,#510,.F.);
#747=ORIENTED_EDGE('',*,*,#670,.T.);
#748=EDGE_LOOP('',(#739,#745,#746,#747));
#749=FACE_BOUND('',#748,.T.);
#750=ADVANCED_FACE('F515',(#749),#738,.F.);
#751=CARTESIAN_POINT('',(-29.,-1.00000000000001,10.));
#752=DIRECTION('',(0.,0.,-1.));
#753=DIRECTION('',(-1.,0.,0.));
#754=AXIS2_PLACEMENT_3D('',#751,#752,#753);
#755=CYLINDRICAL_SURFACE('',#754,3.);
#756=ORIENTED_EDGE('',*,*,#554,.F.);
#757=ORIENTED_EDGE('',*,*,#693,.F.);
#758=ORIENTED_EDGE('',*,*,#443,.F.);
#759=ORIENTED_EDGE('',*,*,#727,.F.);
#760=EDGE_LOOP('',(#756,#757,#758,#759));
#761=FACE_BOUND('',#760,.T.);
#762=ADVANCED_FACE('F507',(#761),#755,.F.);
#763=CARTESIAN_POINT('',(29.,-0.999999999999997,10.));
#764=DIRECTION('',(0.,0.,-1.));
#765=DIRECTION('',(-1.,0.,0.));
#766=AXIS2_PLACEMENT_3D('',#763,#764,#765);
#767=CYLINDRICAL_SURFACE('',#766,3.);
#768=ORIENTED_EDGE('',*,*,#519,.F.);
#769=ORIENTED_EDGE('',*,*,#744,.F.);
#770=ORIENTED_EDGE('',*,*,#409,.F.);
#771=ORIENTED_EDGE('',*,*,#710,.F.);
#772=EDGE_LOOP('',(#768,#769,#770,#771));
#773=FACE_BOUND('',#772,.T.);
#774=ADVANCED_FACE('F464',(#773),#767,.F.);
#775=CARTESIAN_POINT('',(0.,6.,8.));
#776=DIRECTION('',(0.,0.,1.));
#777=DIRECTION('',(1.,0.,0.));
#778=AXIS2_PLACEMENT_3D('',#775,#776,#777);
#779=CYLINDRICAL_SURFACE('',#778,6.);
#780=CARTESIAN_POINT('',(0.,12.,23.));
#781=CARTESIAN_POINT('',(0.0788941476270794,11.9999993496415,22.9999991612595));
#782=CARTESIAN_POINT('',(0.157796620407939,11.9984386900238,22.9968820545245));
#783=CARTESIAN_POINT('',(0.315001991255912,11.9922435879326,22.98446072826));
#784=CARTESIAN_POINT('',(0.393304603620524,11.987607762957,22.9751537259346));
#785=CARTESIAN_POINT('',(0.626628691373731,11.9692197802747,22.9380421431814));
#786=CARTESIAN_POINT('',(0.77995289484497,11.950987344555,22.9010471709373));
#787=CARTESIAN_POINT('',(1.07683586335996,11.9044896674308,22.8044182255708));
#788=CARTESIAN_POINT('',(1.22043005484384,11.8762634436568,22.7448722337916));
#789=CARTESIAN_POINT('',(1.49540820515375,11.8123730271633,22.6052887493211));
#790=CARTESIAN_POINT('',(1.62679312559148,11.7767094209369,22.5252528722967));
#791=CARTESIAN_POINT('',(1.88252701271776,11.6986875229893,22.3414460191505));
#792=CARTESIAN_POINT('',(2.00596945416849,11.6560547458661,22.2365320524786));
#793=CARTESIAN_POINT('',(2.23433451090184,11.5698003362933,22.0084440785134));
#794=CARTESIAN_POINT('',(2.33924301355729,11.5261779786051,21.8852562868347));
#795=CARTESIAN_POINT('',(2.53576864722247,11.4389634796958,21.6125156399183));
#796=CARTESIAN_POINT('',(2.625724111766,11.3956360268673,21.4616590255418));
#797=CARTESIAN_POINT('',(2.74034031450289,11.337824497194,21.2240491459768));
#798=CARTESIAN_POINT('',(2.77516786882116,11.3197457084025,21.1429290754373));
#799=CARTESIAN_POINT('',(2.83769299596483,11.2866576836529,20.9773994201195));
#800=CARTESIAN_POINT('',(2.86539478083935,11.2716466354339,20.8929918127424));
#801=CARTESIAN_POINT('',(2.91188280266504,11.2461034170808,20.7266042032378));
#802=CARTESIAN_POINT('',(2.93110042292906,11.235358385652,20.6447772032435));
#803=CARTESIAN_POINT('',(2.96263559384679,11.2175778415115,20.4794450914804));
#804=CARTESIAN_POINT('',(2.97495680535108,11.2105403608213,20.3959408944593));
#805=CARTESIAN_POINT('',(2.99251382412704,11.2004775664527,20.2279936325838));
#806=CARTESIAN_POINT('',(2.99775389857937,11.1974498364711,20.1435511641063));
#807=CARTESIAN_POINT('',(3.00108452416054,11.1955255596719,19.9745063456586));
#808=CARTESIAN_POINT('',(2.99917575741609,11.1966286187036,19.8899040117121));
#809=CARTESIAN_POINT('',(2.98404973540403,11.2053466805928,19.6572461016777));
#810=CARTESIAN_POINT('',(2.96335042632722,11.2172679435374,19.5097558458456));
#811=CARTESIAN_POINT('',(2.90082280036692,11.2522818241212,19.2208063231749));
#812=CARTESIAN_POINT('',(2.85898775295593,11.2753780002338,19.0793489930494));
#813=CARTESIAN_POINT('',(2.75462843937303,11.3306256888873,18.8023203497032));
#814=CARTESIAN_POINT('',(2.69164495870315,11.36297559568,18.6669628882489));
#815=CARTESIAN_POINT('',(2.54712530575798,11.4331017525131,18.408095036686));
#816=CARTESIAN_POINT('',(2.46558080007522,11.4708804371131,18.2845900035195));
#817=CARTESIAN_POINT('',(2.27419808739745,11.5533948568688,18.0364369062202));
#818=CARTESIAN_POINT('',(2.16208335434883,11.5984053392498,17.9136295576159));
#819=CARTESIAN_POINT('',(1.918666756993,11.6864286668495,17.6877935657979));
#820=CARTESIAN_POINT('',(1.78735577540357,11.7294405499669,17.5847743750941));
#821=CARTESIAN_POINT('',(1.501549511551,11.8110596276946,17.3969430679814));
#822=CARTESIAN_POINT('',(1.34626077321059,11.8493695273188,17.3131985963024));
#823=CARTESIAN_POINT('',(1.02139864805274,11.9147364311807,17.1737088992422));
#824=CARTESIAN_POINT('',(0.85183672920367,11.9418023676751,17.1179414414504));
#825=CARTESIAN_POINT('',(0.518299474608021,11.9797300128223,17.0405737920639));
#826=CARTESIAN_POINT('',(0.355024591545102,11.9917481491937,17.0165262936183));
#827=CARTESIAN_POINT('',(0.0263387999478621,12.0021904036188,16.9956058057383));
#828=CARTESIAN_POINT('',(-0.139071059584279,12.0006209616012,16.9987199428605));
#829=CARTESIAN_POINT('',(-0.453698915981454,11.9847357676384,17.0306200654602));
#830=CARTESIAN_POINT('',(-0.60317822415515,11.9714173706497,17.0573975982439));
#831=CARTESIAN_POINT('',(-0.895220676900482,11.9346651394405,17.1327142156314));
#832=CARTESIAN_POINT('',(-1.03778305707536,11.911230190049,17.1812556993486));
#833=CARTESIAN_POINT('',(-1.31666582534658,11.8555275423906,17.2999953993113));
#834=CARTESIAN_POINT('',(-1.45269119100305,11.8230264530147,17.3707731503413));
#835=CARTESIAN_POINT('',(-1.7113840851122,11.7523192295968,17.5313226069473));
#836=CARTESIAN_POINT('',(-1.83404588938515,11.7141106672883,17.6211024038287));
#837=CARTESIAN_POINT('',(-2.07530306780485,11.6312466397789,17.8272812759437));
#838=CARTESIAN_POINT('',(-2.19231623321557,11.5863265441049,17.9454286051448));
#839=CARTESIAN_POINT('',(-2.40556896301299,11.497871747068,18.1997754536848));
#840=CARTESIAN_POINT('',(-2.50179415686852,11.4543380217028,18.3359873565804));
#841=CARTESIAN_POINT('',(-2.67512374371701,11.3715357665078,18.6309309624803));
#842=CARTESIAN_POINT('',(-2.75107648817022,11.3325758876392,18.7904337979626));
#843=CARTESIAN_POINT('',(-2.87424847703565,11.2672221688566,19.1225302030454));
#844=CARTESIAN_POINT('',(-2.92150474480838,11.2408121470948,19.2951065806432));
#845=CARTESIAN_POINT('',(-2.98158506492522,11.2068450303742,19.6307306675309));
#846=CARTESIAN_POINT('',(-2.99727899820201,11.1977215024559,19.7931027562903));
#847=CARTESIAN_POINT('',(-3.00206745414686,11.1949606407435,20.1183412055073));
#848=CARTESIAN_POINT('',(-2.99117350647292,11.2013165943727,20.2812073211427));
#849=CARTESIAN_POINT('',(-2.94577840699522,11.227135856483,20.5864504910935));
#850=CARTESIAN_POINT('',(-2.91362505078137,11.2452928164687,20.7293013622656));
#851=CARTESIAN_POINT('',(-2.8295259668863,11.2911305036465,21.0074244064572));
#852=CARTESIAN_POINT('',(-2.77757387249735,11.3188142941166,21.142694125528));
#853=CARTESIAN_POINT('',(-2.65144766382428,11.3828558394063,21.4118743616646));
#854=CARTESIAN_POINT('',(-2.57601505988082,11.4196713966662,21.5450829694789));
#855=CARTESIAN_POINT('',(-2.4064512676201,11.4970602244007,21.7978243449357));
#856=CARTESIAN_POINT('',(-2.3123103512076,11.5376354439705,21.9173499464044));
#857=CARTESIAN_POINT('',(-2.09461689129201,11.6238685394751,22.1544228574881));
#858=CARTESIAN_POINT('',(-1.9688805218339,11.6695449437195,22.2699651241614));
#859=CARTESIAN_POINT('',(-1.69843715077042,11.7563371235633,22.478801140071));
#860=CARTESIAN_POINT('',(-1.55371998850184,11.7974504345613,22.5720828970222));
#861=CARTESIAN_POINT('',(-1.32452333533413,11.8525140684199,22.6931781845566));
#862=CARTESIAN_POINT('',(-1.24575314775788,11.8698252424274,22.7305202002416));
#863=CARTESIAN_POINT('',(-1.0847972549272,11.9016884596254,22.7983616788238));
#864=CARTESIAN_POINT('',(-1.00261324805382,11.9162418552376,22.8288644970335));
#865=CARTESIAN_POINT('',(-0.835616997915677,11.9421269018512,22.8826072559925));
#866=CARTESIAN_POINT('',(-0.7508109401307,11.9534655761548,22.905863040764));
#867=CARTESIAN_POINT('',(-0.579142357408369,11.9726077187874,22.9448825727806));
#868=CARTESIAN_POINT('',(-0.492281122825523,11.9804133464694,22.9606508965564));
#869=CARTESIAN_POINT('',(-0.337824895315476,11.9908582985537,22.9816846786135));
#870=CARTESIAN_POINT('',(-0.270495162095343,11.9942803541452,22.988546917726));
#871=CARTESIAN_POINT('',(-0.135445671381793,11.9988515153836,22.9977050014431));
#872=CARTESIAN_POINT('',(-0.0677259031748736,12.0000005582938,23.0000007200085));
#873=CARTESIAN_POINT('',(0.,12.,23.));
#874=B_SPLINE_CURVE_WITH_KNOTS('',3,(#780,#781,#782,#783,#784,#785,#786,#787,#788,#789,#790,
#791,#792,#793,#794,#795,#796,#797,#798,#799,#800,#801,#802,#803,#804,#805,#806,#807,#808,#809,
#810,#811,#812,#813,#814,#815,#816,#817,#818,#819,#820,#821,#822,#823,#824,#825,#826,#827,#828,
#829,#830,#831,#832,#833,#834,#835,#836,#837,#838,#839,#840,#841,#842,#843,#844,#845,#846,#847,
#848,#849,#850,#851,#852,#853,#854,#855,#856,#857,#858,#859,#860,#861,#862,#863,#864,#865,#866,
#867,#868,#869,#870,#871,#872,#873),.UNSPECIFIED.,.T.,.F.,(4,2,2,2,2,2,2,2,2,2,2,2,2,2,2,2,2,2,
2,2,2,2,2,2,2,2,2,2,2,2,2,2,2,2,2,2,2,2,2,2,2,2,2,2,2,2,4),(0.,0.236611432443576,
0.4733293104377,0.947100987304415,1.41904300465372,1.89094781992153,2.39140181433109,
2.89223525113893,3.4319083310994,3.70192714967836,3.97178599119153,4.22563720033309,
4.47935352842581,4.73291689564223,4.98645606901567,5.4323867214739,5.87845946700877,
6.33492255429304,6.79159098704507,7.30616358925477,7.82098138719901,8.35970601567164,
8.8980018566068,9.39171406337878,9.88519228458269,10.3404225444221,10.7957029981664,
11.2640010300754,11.7324988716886,12.2470036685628,12.7618630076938,13.3016558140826,
13.8407507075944,14.3280945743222,14.8152271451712,15.2559532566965,15.6968212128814,
16.1673090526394,16.6380421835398,17.1659726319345,17.6941868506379,17.9605054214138,
18.2266930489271,18.4922945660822,18.7577335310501,18.9608446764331,19.1639614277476),.UNSPECIFIED.);
#875=CARTESIAN_POINT('',(0.,12.,23.));
#876=VERTEX_POINT('',#875);
#877=EDGE_CURVE('E438',#876,#876,#874,.T.);
#878=ORIENTED_EDGE('',*,*,#877,.T.);
#879=EDGE_LOOP('',(#878));
#880=FACE_BOUND('',#879,.T.);
#881=CARTESIAN_POINT('',(0.,6.,8.));
#882=DIRECTION('',(0.,0.,1.));
#883=DIRECTION('',(1.,0.,0.));
#884=AXIS2_PLACEMENT_3D('',#881,#882,#883);
#885=CIRCLE('',#884,6.);
#886=CARTESIAN_POINT('',(6.,6.,8.));
#887=VERTEX_POINT('',#886);
#888=EDGE_CURVE('E469',#887,#887,#885,.T.);
#889=ORIENTED_EDGE('',*,*,#888,.F.);
#890=EDGE_LOOP('',(#889));
#891=FACE_BOUND('',#890,.T.);
#892=ORIENTED_EDGE('',*,*,#364,.T.);
#893=EDGE_LOOP('',(#892));
#894=FACE_BOUND('',#893,.T.);
#895=ADVANCED_FACE('F280',(#880,#891,#894),#779,.F.);
#896=CARTESIAN_POINT('',(0.,6.,8.));
#897=DIRECTION('',(0.,0.,1.));
#898=DIRECTION('',(1.,0.,0.));
#899=AXIS2_PLACEMENT_3D('',#896,#897,#898);
#900=PLANE('',#899);
#901=ORIENTED_EDGE('',*,*,#888,.T.);
#902=EDGE_LOOP('',(#901));
#903=FACE_BOUND('',#902,.T.);
#904=ADVANCED_FACE('F271',(#903),#900,.T.);
#905=CARTESIAN_POINT('',(0.,22.,20.));
#906=DIRECTION('',(0.,1.,0.));
#907=DIRECTION('',(0.,0.,1.));
#908=AXIS2_PLACEMENT_3D('',#905,#906,#907);
#909=CYLINDRICAL_SURFACE('',#908,5.);
#910=CARTESIAN_POINT('',(0.,18.,20.));
#911=DIRECTION('',(0.,1.,0.));
#912=DIRECTION('',(0.,0.,1.));
#913=AXIS2_PLACEMENT_3D('',#910,#911,#912);
#914=CIRCLE('',#913,5.);
#915=CARTESIAN_POINT('',(0.,18.,25.));
#916=VERTEX_POINT('',#915);
#917=EDGE_CURVE('E435',#916,#916,#914,.T.);
#918=ORIENTED_EDGE('',*,*,#917,.F.);
#919=EDGE_LOOP('',(#918));
#920=FACE_BOUND('',#919,.T.);
#921=ORIENTED_EDGE('',*,*,#659,.F.);
#922=ORIENTED_EDGE('',*,*,#661,.F.);
#923=EDGE_LOOP('',(#921,#922));
#924=FACE_BOUND('',#923,.T.);
#925=ADVANCED_FACE('F268',(#920,#924),#909,.F.);
#926=CARTESIAN_POINT('',(2.99999999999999,18.,20.));
#927=DIRECTION('',(0.,-1.,0.));
#928=DIRECTION('',(0.,0.,-1.));
#929=AXIS2_PLACEMENT_3D('',#926,#927,#928);
#930=PLANE('',#929);
#931=CARTESIAN_POINT('',(0.,18.,20.));
#932=DIRECTION('',(0.,1.,0.));
#933=DIRECTION('',(0.,0.,1.));
#934=AXIS2_PLACEMENT_3D('',#931,#932,#933);
#935=CIRCLE('',#934,3.);
#936=CARTESIAN_POINT('',(0.,18.,23.));
#937=VERTEX_POINT('',#936);
#938=EDGE_CURVE('E432',#937,#937,#935,.T.);
#939=ORIENTED_EDGE('',*,*,#938,.F.);
#940=EDGE_LOOP('',(#939));
#941=FACE_BOUND('',#940,.T.);
#942=ORIENTED_EDGE('',*,*,#917,.T.);
#943=EDGE_LOOP('',(#942));
#944=FACE_BOUND('',#943,.T.);
#945=ADVANCED_FACE('F270',(#941,#944),#930,.F.);
#946=CARTESIAN_POINT('',(0.,22.,20.));
#947=DIRECTION('',(0.,1.,0.));
#948=DIRECTION('',(0.,0.,1.));
#949=AXIS2_PLACEMENT_3D('',#946,#947,#948);
#950=CYLINDRICAL_SURFACE('',#949,3.);
#951=ORIENTED_EDGE('',*,*,#877,.F.);
#952=EDGE_LOOP('',(#951));
#953=FACE_BOUND('',#952,.T.);
#954=ORIENTED_EDGE('',*,*,#938,.T.);
#955=EDGE_LOOP('',(#954));
#956=FACE_BOUND('',#955,.T.);
#957=ADVANCED_FACE('F277',(#953,#956),#950,.F.);
#958=CARTESIAN_POINT('',(0.,32.9549925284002,24.));
#959=DIRECTION('',(0.,1.,0.));
#960=DIRECTION('',(-1.,0.,0.));
#961=AXIS2_PLACEMENT_3D('',#958,#959,#960);
#962=CYLINDRICAL_SURFACE('',#961,3.);
#963=CARTESIAN_POINT('',(0.,-7.,24.));
#964=DIRECTION('',(0.,1.,0.));
#965=DIRECTION('',(-1.,0.,0.));
#966=AXIS2_PLACEMENT_3D('',#963,#964,#965);
#967=CIRCLE('',#966,3.);
#968=CARTESIAN_POINT('',(-2.99999999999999,-7.,24.));
#969=VERTEX_POINT('',#968);
#970=EDGE_CURVE('E426',#969,#969,#967,.T.);
#971=ORIENTED_EDGE('',*,*,#970,.T.);
#972=EDGE_LOOP('',(#971));
#973=FACE_BOUND('',#972,.T.);
#974=ORIENTED_EDGE('',*,*,#71,.F.);
#975=EDGE_LOOP('',(#974));
#976=FACE_BOUND('',#975,.T.);
#977=ADVANCED_FACE('F449',(#973,#976),#962,.F.);
#978=CARTESIAN_POINT('',(0.,-7.,24.));
#979=DIRECTION('',(0.,-1.,0.));
#980=DIRECTION('',(1.,0.,0.));
#981=AXIS2_PLACEMENT_3D('',#978,#979,#980);
#982=CONICAL_SURFACE('',#981,3.,1.04719755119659);
#983=CARTESIAN_POINT('',(0.,-5.26794919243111,24.));
#984=VERTEX_POINT('',#983);
#985=VERTEX_LOOP('',#984);
#986=FACE_BOUND('',#985,.T.);
#987=ORIENTED_EDGE('',*,*,#970,.F.);
#988=EDGE_LOOP('',(#987));
#989=FACE_BOUND('',#988,.T.);
#990=ADVANCED_FACE('F454',(#986,#989),#982,.F.);
#991=CARTESIAN_POINT('',(0.,32.9549925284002,8.));
#992=DIRECTION('',(0.,1.,0.));
#993=DIRECTION('',(-1.,0.,0.));
#994=AXIS2_PLACEMENT_3D('',#991,#992,#993);
#995=CYLINDRICAL_SURFACE('',#994,3.);
#996=CARTESIAN_POINT('',(0.,-7.,8.));
#997=DIRECTION('',(0.,1.,0.));
#998=DIRECTION('',(-1.,0.,0.));
#999=AXIS2_PLACEMENT_3D('',#996,#997,#998);
#1000=CIRCLE('',#999,3.);
#1001=CARTESIAN_POINT('',(-2.99999999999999,-7.,8.));
#1002=VERTEX_POINT('',#1001);
#1003=EDGE_CURVE('E417',#1002,#1002,#1000,.T.);
#1004=ORIENTED_EDGE('',*,*,#1003,.T.);
#1005=EDGE_LOOP('',(#1004));
#1006=FACE_BOUND('',#1005,.T.);
#1007=ORIENTED_EDGE('',*,*,#107,.F.);
#1008=EDGE_LOOP('',(#1007));
#1009=FACE_BOUND('',#1008,.T.);
#1010=ADVANCED_FACE('F630',(#1006,#1009),#995,.F.);
#1011=CARTESIAN_POINT('',(0.,-7.,8.));
#1012=DIRECTION('',(0.,-1.,0.));
#1013=DIRECTION('',(1.,0.,0.));
#1014=AXIS2_PLACEMENT_3D('',#1011,#1012,#1013);
#1015=CONICAL_SURFACE('',#1014,3.,1.04719755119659);
#1016=CARTESIAN_POINT('',(0.,-5.26794919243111,8.));
#1017=VERTEX_POINT('',#1016);
#1018=VERTEX_LOOP('',#1017);
#1019=FACE_BOUND('',#1018,.T.);
#1020=ORIENTED_EDGE('',*,*,#1003,.F.);
#1021=EDGE_LOOP('',(#1020));
#1022=FACE_BOUND('',#1021,.T.);
#1023=ADVANCED_FACE('F646',(#1019,#1022),#1015,.F.);
#1024=CARTESIAN_POINT('',(8.00000000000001,-21.,0.));
#1025=DIRECTION('',(0.,-1.,0.));
#1026=DIRECTION('',(0.,0.,-1.));
#1027=AXIS2_PLACEMENT_3D('',#1024,#1025,#1026);
#1028=PLANE('',#1027);
#1029=ORIENTED_EDGE('',*,*,#375,.T.);
#1030=ORIENTED_EDGE('',*,*,#40,.F.);
#1031=ORIENTED_EDGE('',*,*,#469,.F.);
#1032=DIRECTION('',(0.,0.,1.));
#1033=VECTOR('',#1032,1.);
#1034=CARTESIAN_POINT('',(4.00000000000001,-21.,0.));
#1035=LINE('',#1034,#1033);
#1036=EDGE_CURVE('E418',#468,#374,#1035,.T.);
#1037=ORIENTED_EDGE('',*,*,#1036,.T.);
#1038=EDGE_LOOP('',(#1029,#1030,#1031,#1037));
#1039=FACE_BOUND('',#1038,.T.);
#1040=ADVANCED_FACE('F655',(#1039),#1028,.F.);
#1041=CARTESIAN_POINT('',(4.00000000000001,-16.,0.));
#1042=DIRECTION('',(-1.,0.,0.));
#1043=DIRECTION('',(0.,-1.,0.));
#1044=AXIS2_PLACEMENT_3D('',#1041,#1042,#1043);
#1045=PLANE('',#1044);
#1046=ORIENTED_EDGE('',*,*,#383,.T.);
#1047=ORIENTED_EDGE('',*,*,#1036,.F.);
#1048=ORIENTED_EDGE('',*,*,#492,.F.);
#1049=DIRECTION('',(0.,0.,1.));
#1050=VECTOR('',#1049,1.);
#1051=CARTESIAN_POINT('',(4.00000000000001,-16.,0.));
#1052=LINE('',#1051,#1050);
#1053=EDGE_CURVE('E193',#485,#382,#1052,.T.);
#1054=ORIENTED_EDGE('',*,*,#1053,.T.);
#1055=EDGE_LOOP('',(#1046,#1047,#1048,#1054));
#1056=FACE_BOUND('',#1055,.T.);
#1057=ADVANCED_FACE('F723',(#1056),#1045,.F.);
#1058=CARTESIAN_POINT('',(8.00000000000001,-16.,0.));
#1059=DIRECTION('',(0.,1.,0.));
#1060=DIRECTION('',(0.,0.,1.));
#1061=AXIS2_PLACEMENT_3D('',#1058,#1059,#1060);
#1062=PLANE('',#1061);
#1063=ORIENTED_EDGE('',*,*,#389,.T.);
#1064=ORIENTED_EDGE('',*,*,#1053,.F.);
#1065=ORIENTED_EDGE('',*,*,#486,.F.);
#1066=ORIENTED_EDGE('',*,*,#315,.T.);
#1067=EDGE_LOOP('',(#1063,#1064,#1065,#1066));
#1068=FACE_BOUND('',#1067,.T.);
#1069=ADVANCED_FACE('F185',(#1068),#1062,.F.);
#1070=CLOSED_SHELL('',(#58,#111,#167,#202,#249,#280,#302,#329,#351,#457,#496,#538,#570,#682,
#699,#716,#733,#750,#762,#774,#895,#904,#925,#945,#957,#977,#990,#1010,#1023,#1040,#1057,#1069));
#1071=MANIFOLD_SOLID_BREP('B2',#1070);
#1072=ADVANCED_BREP_SHAPE_REPRESENTATION('',(#18,#1071),#14);
#1073=SHAPE_DEFINITION_REPRESENTATION(#9,#1072);
ENDSEC;
END-ISO-10303-21;
